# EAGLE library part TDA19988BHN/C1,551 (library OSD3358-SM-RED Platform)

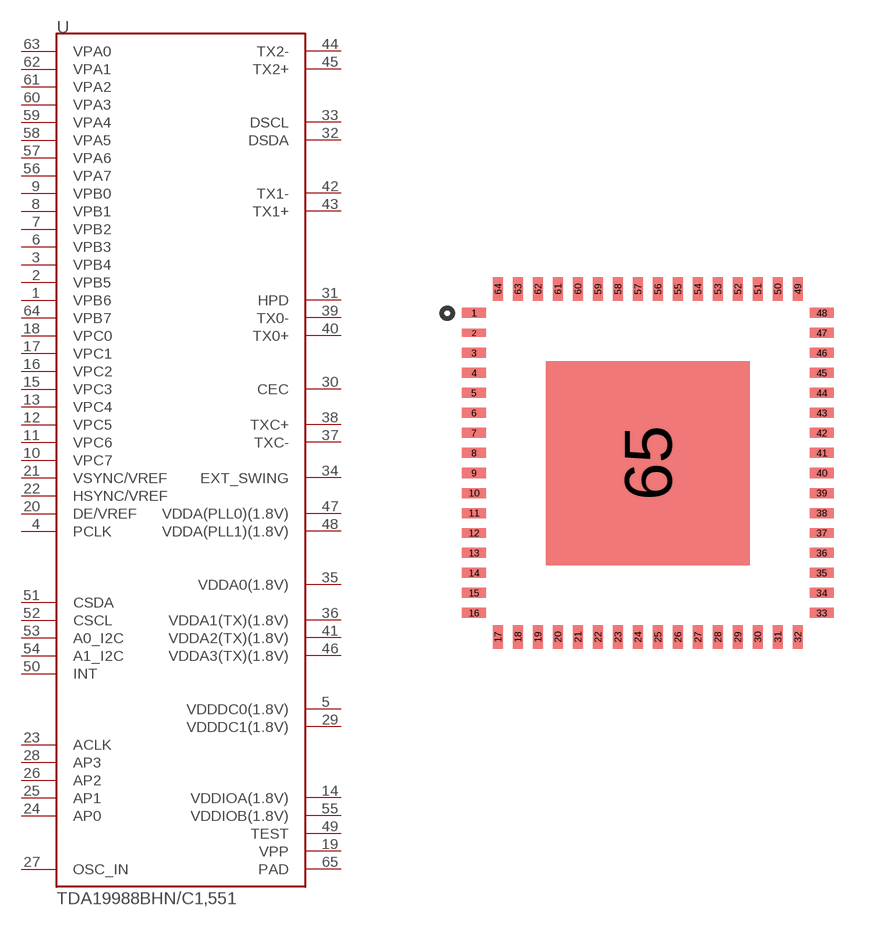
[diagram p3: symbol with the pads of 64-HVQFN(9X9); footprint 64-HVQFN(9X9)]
Designator prefix U

## TDA19988BHN/C1,551  [64-HVQFN(9X9)]
1  VPB6
2  VPB5
3  VPB4
4  PCLK
5  VDDDC0(1.8V)
6  VPB3
7  VPB2
8  VPB1
9  VPB0
10  VPC7
11  VPC6
12  VPC5
13  VPC4
14  VDDIOA(1.8V)
15  VPC3
16  VPC2
17  VPC1
18  VPC0
19  VPP
20  DE/VREF
21  VSYNC/VREF
22  HSYNC/VREF
23  ACLK
24  AP0
25  AP1
26  AP2
27  OSC_IN
28  AP3
29  VDDDC1(1.8V)
30  CEC
31  HPD
32  DSDA
33  DSCL
34  EXT_SWING
35  VDDA0(1.8V)
36  VDDA1(TX)(1.8V)
37  TXC-
38  TXC+
39  TX0-
40  TX0+
41  VDDA2(TX)(1.8V)
42  TX1-
43  TX1+
44  TX2-
45  TX2+
46  VDDA3(TX)(1.8V)
47  VDDA(PLL0)(1.8V)
48  VDDA(PLL1)(1.8V)
49  TEST
50  INT
51  CSDA
52  CSCL
53  A0_I2C
54  A1_I2C
55  VDDIOB(1.8V)
56  VPA7
57  VPA6
58  VPA5
59  VPA4
60  VPA3
61  VPA2
62  VPA1
63  VPA0
64  VPB7
65  PAD

## Footprint 64-HVQFN(9X9) (pad centres in mm)
smd 0.6 x 0.25: 1 -4.35,3.75; 3 -4.35,2.75; 4 -4.35,2.25; 5 -4.35,1.75; 6 -4.35,1.25; 7 -4.35,0.75; 8 -4.35,0.25; 9 -4.35,-0.25; 10 -4.35,-0.75; 11 -4.35,-1.25; 12 -4.35,-1.75; 13 -4.35,-2.25; 14 -4.35,-2.75; 15 -4.35,-3.25; 16 -4.35,-3.75; 33 4.35,-3.75; 34 4.35,-3.25; 35 4.35,-2.75; 36 4.35,-2.25; 37 4.35,-1.75; 38 4.35,-1.25; 39 4.35,-0.75; 40 4.35,-0.25; 41 4.35,0.25; 42 4.35,0.75; 43 4.35,1.25; 44 4.35,1.75; 45 4.35,2.25; 46 4.35,2.75; 47 4.35,3.25; 48 4.35,3.75
smd 0.6 x 0.2: 2 -4.35,3.25
smd 0.25 x 0.6: 17 -3.75,-4.35; 18 -3.25,-4.35; 19 -2.75,-4.35; 20 -2.25,-4.35; 21 -1.75,-4.35; 22 -1.25,-4.35; 23 -0.75,-4.35; 24 -0.25,-4.35; 25 0.25,-4.35; 26 0.75,-4.35; 27 1.25,-4.35; 28 1.75,-4.35; 29 2.25,-4.35; 30 2.75,-4.35; 31 3.25,-4.35; 32 3.75,-4.35; 49 3.75,4.35; 50 3.25,4.35; 51 2.75,4.35; 52 2.25,4.35; 53 1.75,4.35; 54 1.25,4.35; 55 0.75,4.35; 56 0.25,4.35; 57 -0.25,4.35; 58 -0.75,4.35; 59 -1.25,4.35; 60 -1.75,4.35; 61 -2.25,4.35; 62 -2.75,4.35; 63 -3.25,4.35; 64 -3.75,4.35
smd 5.1 x 5.1: 65 0,0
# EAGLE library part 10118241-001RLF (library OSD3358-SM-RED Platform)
Micro-HDMI connector

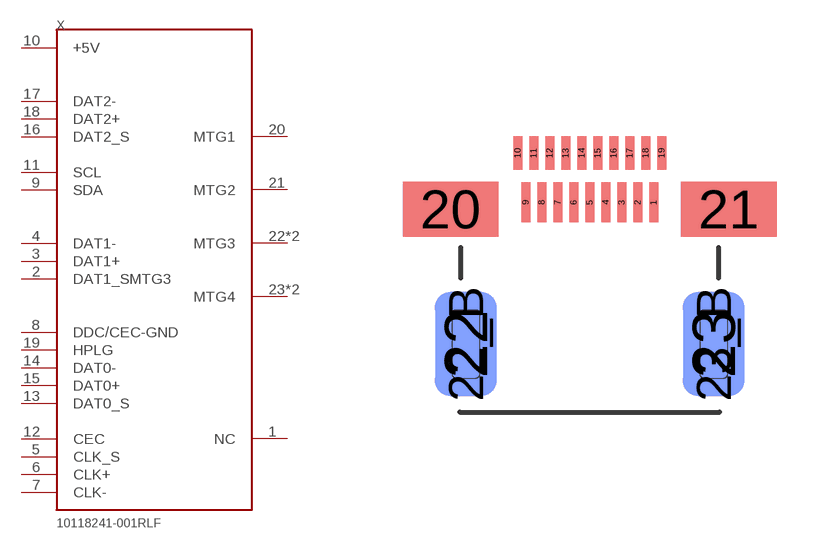
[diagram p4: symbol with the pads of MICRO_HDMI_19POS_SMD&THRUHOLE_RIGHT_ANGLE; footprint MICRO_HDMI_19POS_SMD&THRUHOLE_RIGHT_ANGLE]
Designator prefix X

## 10118241-001RLF  [MICRO_HDMI_19POS_SMD&THRUHOLE_RIGHT_ANGLE]
1  NC  nc
2  DAT1_SMTG3
3  DAT1+
4  DAT1-
5  CLK_S
6  CLK+
7  CLK-
8  DDC/CEC-GND
9  SDA
10  +5V  pwr
11  SCL
12  CEC
13  DAT0_S
14  DAT0-
15  DAT0+
16  DAT2_S
17  DAT2-
18  DAT2+
19  HPLG
20  MTG1  pwr
21  MTG2  pwr
22  MTG3  pwr
22_B  MTG3  pwr
23  MTG4  pwr
23_B  MTG4  pwr

## Footprint MICRO_HDMI_19POS_SMD&THRUHOLE_RIGHT_ANGLE (pad centres in mm)
smd 0.23 x 1: 1 1.6,3.54; 2 1.2,3.54; 3 0.8,3.54; 4 0.4,3.54; 5 0,3.54; 6 -0.4,3.54; 7 -0.8,3.54; 8 -1.2,3.54; 9 -1.6,3.54
smd 0.23 x 0.85: 10 -1.8,4.775; 11 -1.4,4.775; 12 -1,4.775; 13 -0.6,4.775; 14 -0.2,4.775; 15 0.2,4.775; 16 0.6,4.775; 17 1,4.775; 18 1.4,4.775; 19 1.8,4.775
smd 2.4 x 1.38: 20 -3.48,3.37; 21 3.48,3.37
smd 1.55 x 2.6: 22 -3.1,0; 23 3.1,0
smd 1.55 x 2.6 bottom: 22_B -3.1,0; 23_B 3.1,0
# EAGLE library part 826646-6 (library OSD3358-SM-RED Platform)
6-pin 100 mil header

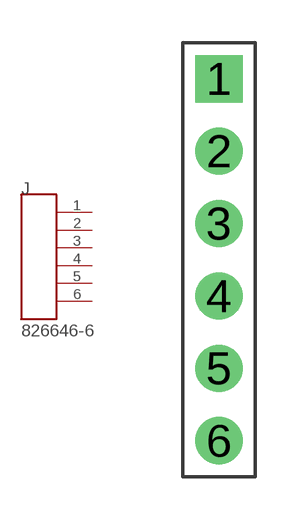
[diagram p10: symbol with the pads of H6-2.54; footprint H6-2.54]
Designator prefix J

## 826646-6 (MPN: P125-1106A1BS116A1; VALUE: 6p-2.54)  [H6-2.54]
1  1
2  2
3  3
4  4
5  5
6  6

## Footprint H6-2.54 (pad centres in mm)
drill 0.889 pad 1.651 square: 1 0,6.35
drill 0.889 pad 1.651: 2 0,3.81; 3 0,1.27; 4 0,-1.27; 5 0,-3.81; 6 0,-6.35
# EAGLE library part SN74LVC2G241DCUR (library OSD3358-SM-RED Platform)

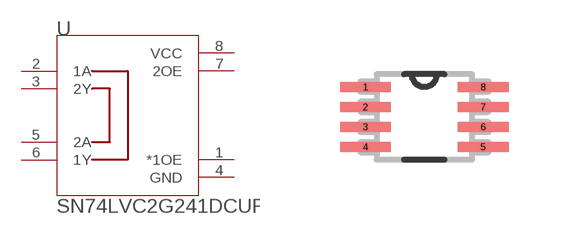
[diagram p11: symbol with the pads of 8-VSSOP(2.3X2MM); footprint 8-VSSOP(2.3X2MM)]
Designator prefix U

## SN74LVC2G241DCUR  [8-VSSOP(2.3X2MM)]
1  *1OE  in
2  1A  in
3  2Y  out
4  GND  pwr
5  2A  in
6  1Y  out
7  2OE  in
8  VCC  pwr

## Footprint 8-VSSOP(2.3X2MM) (pad centres in mm)
smd 1.27 x 0.254: 1 -1.473,0.749; 2 -1.473,0.249; 3 -1.473,-0.249; 4 -1.473,-0.749; 5 1.473,-0.749; 6 1.473,-0.249; 7 1.473,0.249; 8 1.473,0.749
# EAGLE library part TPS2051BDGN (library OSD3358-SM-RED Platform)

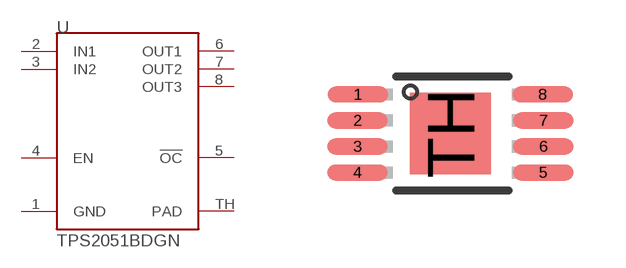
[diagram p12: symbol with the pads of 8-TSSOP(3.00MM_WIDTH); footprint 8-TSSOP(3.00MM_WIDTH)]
Designator prefix U

## TPS2051BDGN  [8-TSSOP(3.00MM_WIDTH)]
1  GND  pwr
2  IN1  in
3  IN2  in
4  EN  in
5  !OC  out
6  OUT1  out
7  OUT2  out
8  OUT3  out
TH  PAD  pwr

## Footprint 8-TSSOP(3.00MM_WIDTH) (pad centres in mm)
DGN (S-PDSO-G8) PowerPAD (TM) Plastic Small-Outline Package Source: http://focus.ti.com/lit/ds/symlink/ths4211.pdf
smd 1.524 x 0.406: 1 -2.311,0.975; 2 -2.324,0.325; 3 -2.324,-0.325; 4 -2.324,-0.975; 5 2.324,-0.975; 6 2.324,-0.325; 7 2.324,0.325; 8 2.311,0.975
smd 2.032 x 2.032: TH 0,0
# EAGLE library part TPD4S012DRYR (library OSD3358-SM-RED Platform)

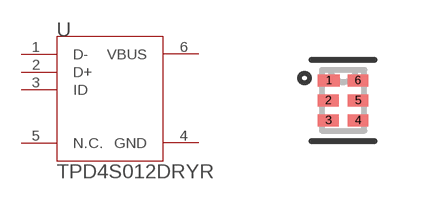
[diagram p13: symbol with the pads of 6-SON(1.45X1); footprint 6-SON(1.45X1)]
Designator prefix U

## TPD4S012DRYR_P1_M (DATASHEETURL: http://www.ti.com/lit/gpn/TPD4S012; FAMILY_NAME: ESD Solution; GENERIC_PART_NUMBER: TPD4S012; INDUSTRY_STD_PKG_TYPE: SON; MANUFACTURER: Texas Instruments; MANUFACTURER_PART_NUMBER: tpd4s012_dry_6; PACKAGE_DESIGNATOR: DRY; PIN_COUNT: 6; VENDOR: Texas Instruments)  [6-SON(1.45X1)]
1  D-  pas
2  D+  pas
3  ID  pas
4  GND  pwr
5  N.C.  nc
6  VBUS  pas

## TPD4S012DRYR_P1_P  [6-SON(1.45X1)]
1  D+  pas
2  D-  pas
3  ID  pas
4  GND  pwr
5  N.C.  nc
6  VBUS  pas

## Footprint 6-SON(1.45X1) (pad centres in mm)
smd 0.55 x 0.3: 1 -0.355,0.5
smd 0.52 x 0.3: 2 -0.37,0; 3 -0.37,-0.5; 4 0.37,-0.5; 5 0.37,0; 6 0.37,0.5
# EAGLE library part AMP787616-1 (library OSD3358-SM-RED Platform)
USB connector (horizontal)

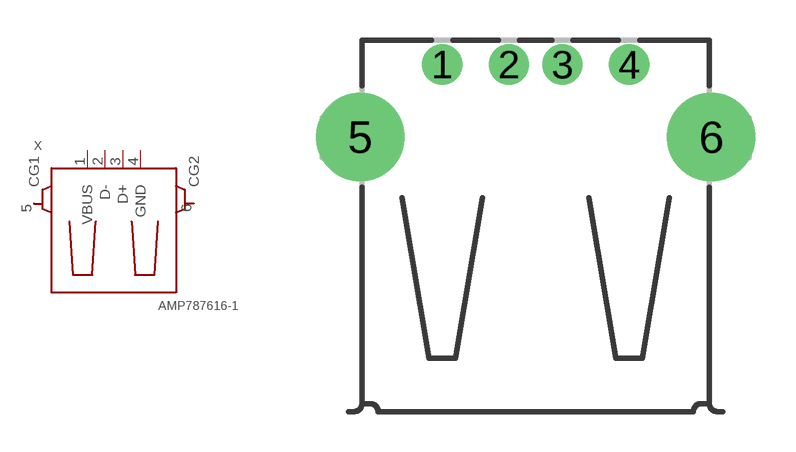
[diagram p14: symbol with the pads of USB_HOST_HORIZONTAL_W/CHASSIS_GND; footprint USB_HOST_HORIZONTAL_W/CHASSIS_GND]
Designator prefix X

## AMP787616-1  [USB_HOST_HORIZONTAL_W/CHASSIS_GND]
1  VBUS
2  D-
3  D+
4  GND
5  CG1
6  CG2

## Footprint USB_HOST_HORIZONTAL_W/CHASSIS_GND (pad centres in mm)
drill 1: 1 -3.5,12.99; 2 -1,12.99; 3 1,12.99; 4 3.5,12.99
drill 2.3: 5 -6.57,10.28; 6 6.57,10.28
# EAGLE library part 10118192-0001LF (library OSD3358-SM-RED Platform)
Amphenol FCI Micro USB Type B Complete Surface Mount (SMT) no guide holes

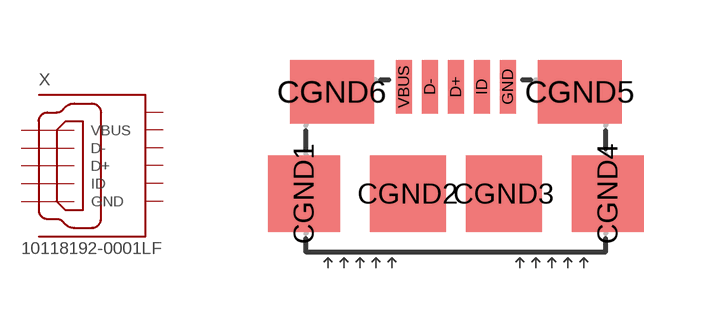
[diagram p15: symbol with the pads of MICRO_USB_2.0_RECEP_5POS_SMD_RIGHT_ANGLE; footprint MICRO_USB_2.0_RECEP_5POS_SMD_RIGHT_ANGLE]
Designator prefix X

## 10118192-0001LF  [MICRO_USB_2.0_RECEP_5POS_SMD_RIGHT_ANGLE]
CGND1  SGND1
CGND2  SGND2
CGND3  SGND3
CGND4  SGND4
CGND5  SGND5
CGND6  SGND6
D+  D+  in
D-  D-  in
GND  GND  in
ID  ID  in
VBUS  VBUS  in

## Footprint MICRO_USB_2.0_RECEP_5POS_SMD_RIGHT_ANGLE (pad centres in mm)
smd 1.8 x 1.9: CGND1 -3.8,0; CGND4 3.8,0
smd 1.9 x 1.9: CGND2 -1.2,0; CGND3 1.2,0
smd 2.1 x 1.6: CGND5 3.1,2.55; CGND6 -3.1,2.55
smd 0.4 x 1.35: D+ 0,2.675; D- -0.65,2.675; GND 1.3,2.675; ID 0.65,2.675; VBUS -1.3,2.675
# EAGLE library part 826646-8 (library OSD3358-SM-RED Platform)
8-pin 100 mil header

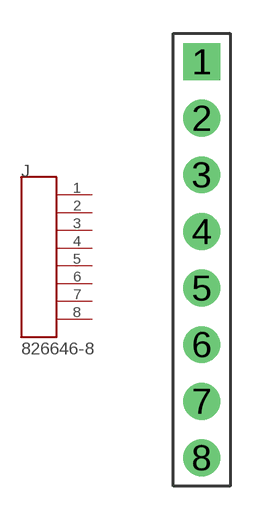
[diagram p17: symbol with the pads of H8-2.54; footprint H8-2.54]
Designator prefix J

## 826646-8  [H8-2.54]
1  1
2  2
3  3
4  4
5  5
6  6
7  7
8  8

## Footprint H8-2.54 (pad centres in mm)
drill 0.889 pad 1.651 square: 1 0,8.89
drill 0.889 pad 1.651: 2 0,6.35; 3 0,3.81; 4 0,1.27; 5 0,-1.27; 6 0,-3.81; 7 0,-6.35; 8 0,-8.89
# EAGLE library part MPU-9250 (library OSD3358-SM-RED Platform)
314990005

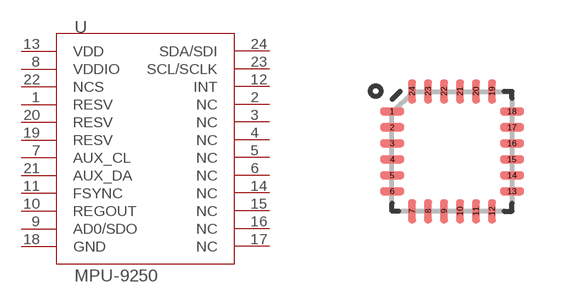
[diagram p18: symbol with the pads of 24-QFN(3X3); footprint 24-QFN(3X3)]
Designator prefix U

## MPU-9250 (MPN: MPU-9250; VALUE: MPU-9250)  [24-QFN(3X3)]
1  RESV
2  NC
3  NC
4  NC
5  NC
6  NC
7  AUX_CL
8  VDDIO
9  AD0/SDO
10  REGOUT
11  FSYNC
12  INT
13  VDD
14  NC
15  NC
16  NC
17  NC
18  GND
19  RESV
20  RESV
21  AUX_DA
22  NCS
23  SCL/SCLK
24  SDA/SDI

## Footprint 24-QFN(3X3) (pad centres in mm)
smd 0.6 x 0.2: 1 -1.5,1; 2 -1.5,0.6; 3 -1.5,0.2; 4 -1.5,-0.2; 5 -1.5,-0.6; 6 -1.5,-1; 13 1.5,-1; 14 1.5,-0.6; 15 1.5,-0.2; 16 1.5,0.2; 17 1.5,0.6; 18 1.5,1
smd 0.2 x 0.6: 7 -1,-1.5; 8 -0.6,-1.5; 9 -0.2,-1.5; 10 0.2,-1.5; 11 0.6,-1.5; 12 1,-1.5; 19 1,1.5; 20 0.6,1.5; 21 0.2,1.5; 22 -0.2,1.5; 23 -0.6,1.5; 24 -1,1.5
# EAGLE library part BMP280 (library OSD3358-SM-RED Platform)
BOSCH BMP280 Digital Pressure Sensor

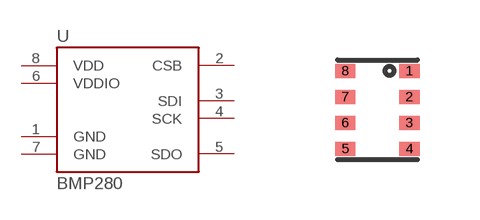
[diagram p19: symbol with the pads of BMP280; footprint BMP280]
Designator prefix U

## BMP280  [BMP280]
1  GND  pwr
2  CSB  in
3  SDI
4  SCK  in
5  SDO
6  VDDIO  in
7  GND  pwr
8  VDD  pwr

## Footprint BMP280 (pad centres in mm)
smd 0.5 x 0.35: 1 0.8,0.975; 2 0.8,0.325; 3 0.8,-0.325; 4 0.8,-0.975; 5 -0.8,-0.975; 6 -0.8,-0.325; 7 -0.8,0.325; 8 -0.8,0.975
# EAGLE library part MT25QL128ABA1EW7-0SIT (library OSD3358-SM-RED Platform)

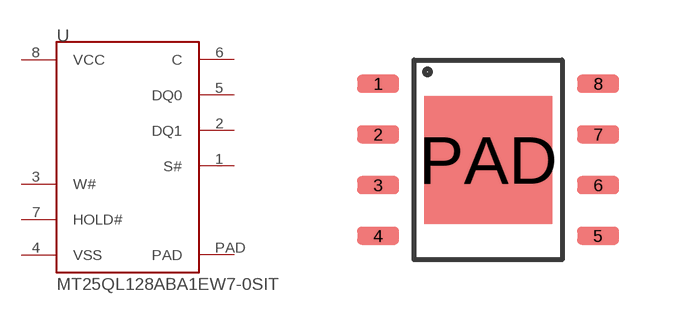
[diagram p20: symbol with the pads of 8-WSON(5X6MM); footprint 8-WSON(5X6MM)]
Designator prefix U

## MT25QL128ABA1EW7-0SIT  [8-WSON(5X6MM)]
1  S#
2  DQ1
3  W#
4  VSS
5  DQ0
6  C
7  HOLD#
8  VCC
PAD  PAD

## Footprint 8-WSON(5X6MM) (pad centres in mm)
smd 1.05 x 0.45: 1 -2.75,1.905; 2 -2.75,0.635; 3 -2.75,-0.635; 4 -2.75,-1.905; 5 2.75,-1.905; 6 2.75,-0.635; 7 2.75,0.635; 8 2.75,1.905
smd 3.2 x 3.2: PAD 0,0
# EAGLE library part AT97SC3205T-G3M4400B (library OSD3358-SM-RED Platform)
Trusted Platform Module

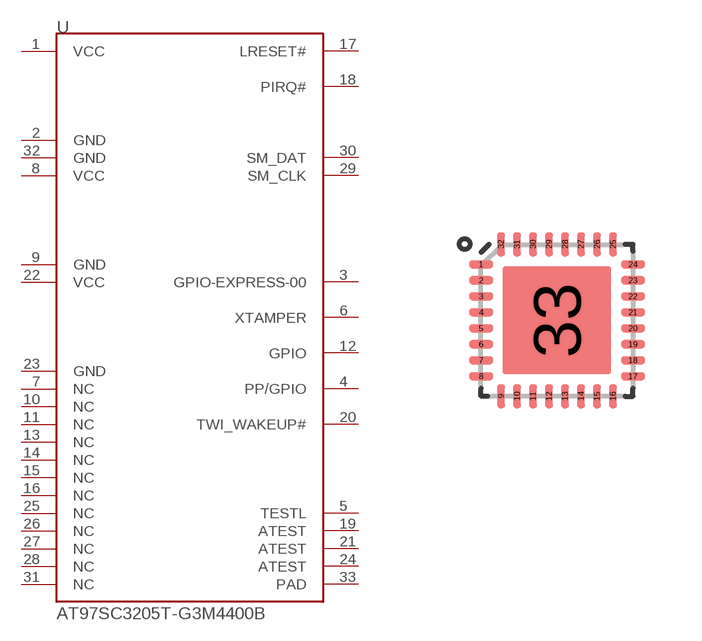
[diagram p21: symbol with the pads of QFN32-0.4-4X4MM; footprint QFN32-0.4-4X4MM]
Designator prefix U

## AT97SC3205T-G3M4400B  [QFN32-0.4-4X4MM]
1  VCC
2  GND
3  GPIO-EXPRESS-00
4  PP/GPIO
5  TESTL
6  XTAMPER
7  NC
8  VCC
9  GND
10  NC
11  NC
12  GPIO
13  NC
14  NC
15  NC
16  NC
17  LRESET#
18  PIRQ#
19  ATEST
20  TWI_WAKEUP#
21  ATEST
22  VCC
23  GND
24  ATEST
25  NC
26  NC
27  NC
28  NC
29  SM_CLK
30  SM_DAT
31  NC
32  GND
33  PAD

## Footprint QFN32-0.4-4X4MM (pad centres in mm)
smd 0.6 x 0.2: 1 -1.9,1.4; 2 -1.9,1; 3 -1.9,0.6; 4 -1.9,0.2; 5 -1.9,-0.2; 6 -1.9,-0.6; 7 -1.9,-1; 8 -1.9,-1.4; 17 1.9,-1.4; 18 1.9,-1; 19 1.9,-0.6; 20 1.9,-0.2; 21 1.9,0.2; 22 1.9,0.6; 23 1.9,1; 24 1.9,1.4
smd 0.2 x 0.6: 9 -1.4,-1.9; 10 -1,-1.9; 11 -0.6,-1.9; 12 -0.2,-1.9; 13 0.2,-1.9; 14 0.6,-1.9; 15 1,-1.9; 16 1.4,-1.9; 25 1.4,1.9; 26 1,1.9; 27 0.6,1.9; 28 0.2,1.9; 29 -0.2,1.9; 30 -0.6,1.9; 31 -1,1.9; 32 -1.4,1.9
smd 2.7 x 2.7: 33 0,0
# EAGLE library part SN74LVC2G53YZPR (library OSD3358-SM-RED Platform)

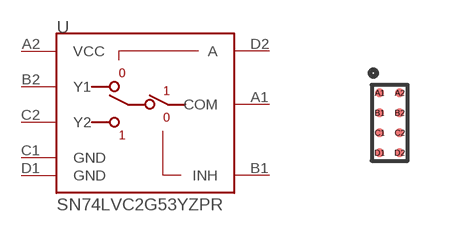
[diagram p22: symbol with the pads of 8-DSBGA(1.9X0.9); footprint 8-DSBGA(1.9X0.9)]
Designator prefix U

## SN74LVC2G53YZPR  [8-DSBGA(1.9X0.9)]
A1  COM
A2  VCC
B1  INH
B2  Y1
C1  GND
C2  Y2
D1  GND
D2  A

## Footprint 8-DSBGA(1.9X0.9) (pad centres in mm)
smd 0.23 x 0.23: A1 -0.25,0.75; A2 0.25,0.75; B1 -0.25,0.25; B2 0.25,0.25; C1 -0.25,-0.25; C2 0.25,-0.25; D1 -0.25,-0.75; D2 0.25,-0.75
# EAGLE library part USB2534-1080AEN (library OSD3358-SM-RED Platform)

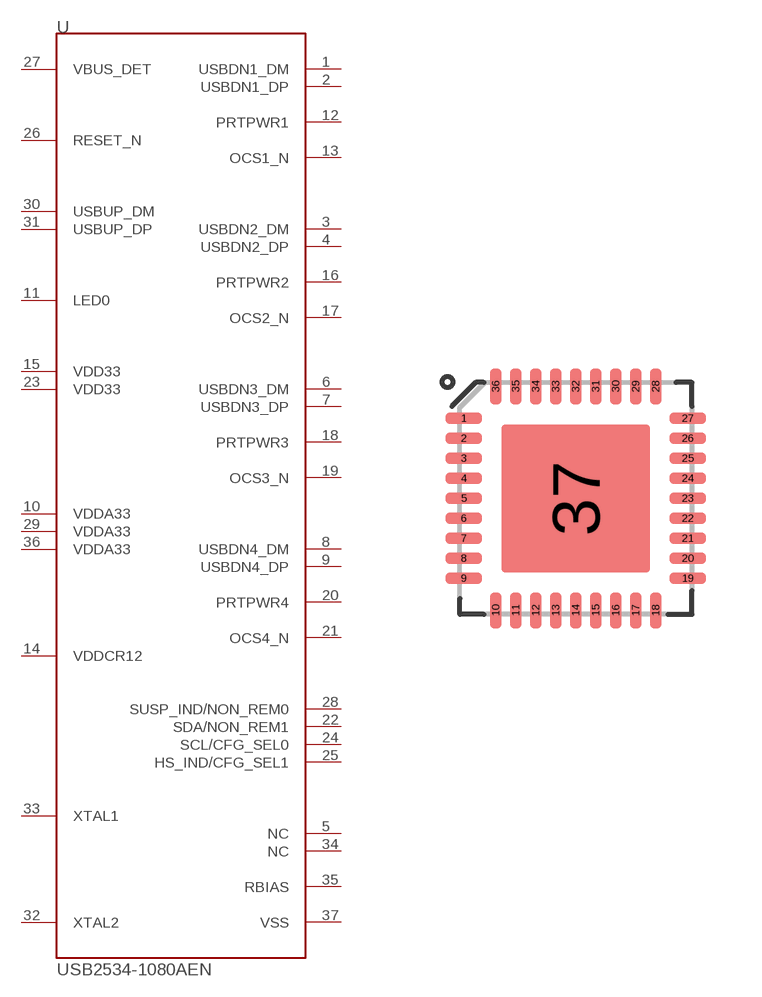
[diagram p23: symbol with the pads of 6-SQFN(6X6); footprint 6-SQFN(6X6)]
Designator prefix U

## USB2534-1080AEN  [6-SQFN(6X6)]
1  USBDN1_DM
2  USBDN1_DP
3  USBDN2_DM
4  USBDN2_DP
5  NC
6  USBDN3_DM
7  USBDN3_DP
8  USBDN4_DM
9  USBDN4_DP
10  VDDA33
11  LED0
12  PRTPWR1
13  OCS1_N
14  VDDCR12
15  VDD33
16  PRTPWR2
17  OCS2_N
18  PRTPWR3
19  OCS3_N
20  PRTPWR4
21  OCS4_N
22  SDA/NON_REM1
23  VDD33
24  SCL/CFG_SEL0
25  HS_IND/CFG_SEL1
26  RESET_N
27  VBUS_DET
28  SUSP_IND/NON_REM0
29  VDDA33
30  USBUP_DM
31  USBUP_DP
32  XTAL2
33  XTAL1
34  NC
35  RBIAS
36  VDDA33
37  VSS

## Footprint 6-SQFN(6X6) (pad centres in mm)
smd 0.9 x 0.28: 1 -2.8,2; 2 -2.8,1.5; 3 -2.8,1; 4 -2.8,0.5; 5 -2.8,0; 6 -2.8,-0.5; 7 -2.8,-1; 8 -2.8,-1.5; 9 -2.8,-2; 19 2.8,-2; 20 2.8,-1.5; 21 2.8,-1; 22 2.8,-0.5; 23 2.8,0; 24 2.8,0.5; 25 2.8,1; 26 2.8,1.5; 27 2.8,2
smd 0.28 x 0.9: 10 -2,-2.8; 11 -1.5,-2.8; 12 -1,-2.8; 13 -0.5,-2.8; 14 0,-2.8; 15 0.5,-2.8; 16 1,-2.8; 17 1.5,-2.8; 18 2,-2.8; 28 2,2.8; 29 1.5,2.8; 30 1,2.8; 31 0.5,2.8; 32 0,2.8; 33 -0.5,2.8; 34 -1,2.8; 35 -1.5,2.8; 36 -2,2.8
smd 3.7 x 3.7: 37 0,0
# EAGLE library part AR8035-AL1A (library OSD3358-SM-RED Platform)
Ethernet PHY (10/100/1000)

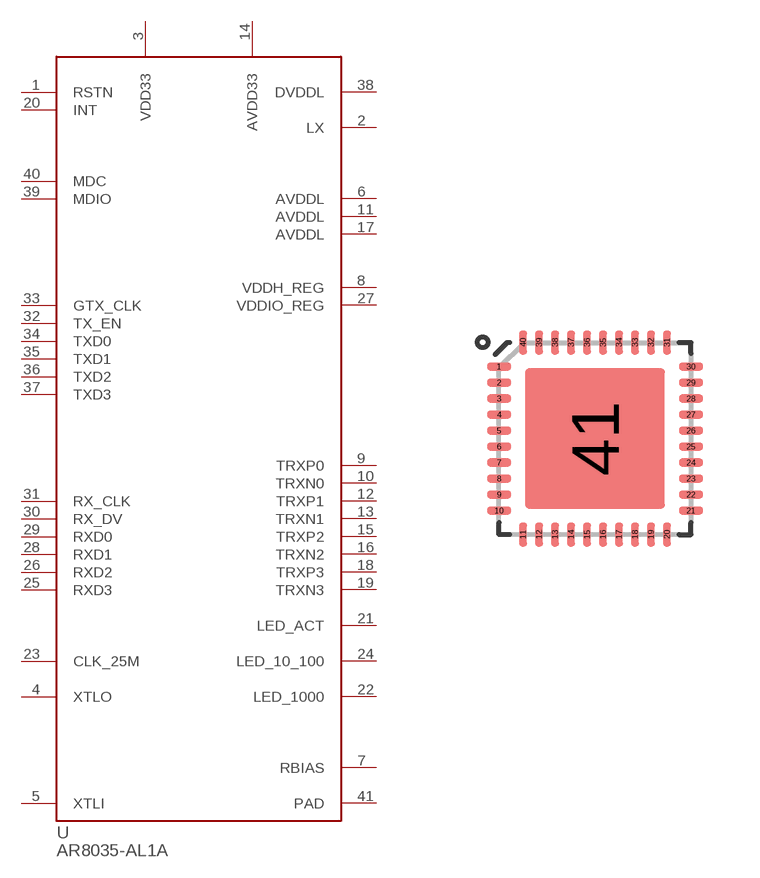
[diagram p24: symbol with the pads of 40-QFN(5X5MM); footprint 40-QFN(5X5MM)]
Designator prefix U

## AR8035-AL1A  [40-QFN(5X5MM)]
1  RSTN
2  LX
3  VDD33
4  XTLO
5  XTLI
6  AVDDL
7  RBIAS
8  VDDH_REG
9  TRXP0
10  TRXN0
11  AVDDL
12  TRXP1
13  TRXN1
14  AVDD33
15  TRXP2
16  TRXN2
17  AVDDL
18  TRXP3
19  TRXN3
20  INT
21  LED_ACT
22  LED_1000
23  CLK_25M
24  LED_10_100
25  RXD3
26  RXD2
27  VDDIO_REG
28  RXD1
29  RXD0
30  RX_DV
31  RX_CLK
32  TX_EN
33  GTX_CLK
34  TXD0
35  TXD1
36  TXD2
37  TXD3
38  DVDDL
39  MDIO
40  MDC
41  PAD

## Footprint 40-QFN(5X5MM) (pad centres in mm)
smd 0.6 x 0.2: 1 -2.4,1.8; 2 -2.4,1.4; 3 -2.4,1; 4 -2.4,0.6; 5 -2.4,0.2; 6 -2.4,-0.2; 7 -2.4,-0.6; 8 -2.4,-1; 9 -2.4,-1.4; 10 -2.4,-1.8; 21 2.4,-1.8; 22 2.4,-1.4; 23 2.4,-1; 24 2.4,-0.6; 25 2.4,-0.2; 26 2.4,0.2; 27 2.4,0.6; 28 2.4,1; 29 2.4,1.4; 30 2.4,1.8
smd 0.2 x 0.6: 11 -1.8,-2.4; 12 -1.4,-2.4; 13 -1,-2.4; 14 -0.6,-2.4; 15 -0.2,-2.4; 16 0.2,-2.4; 17 0.6,-2.4; 18 1,-2.4; 19 1.4,-2.4; 20 1.8,-2.4; 31 1.8,2.4; 32 1.4,2.4; 33 1,2.4; 34 0.6,2.4; 35 0.2,2.4; 36 -0.2,2.4; 37 -0.6,2.4; 38 -1,2.4; 39 -1.4,2.4; 40 -1.8,2.4
smd 3.5 x 3.5: 41 0,0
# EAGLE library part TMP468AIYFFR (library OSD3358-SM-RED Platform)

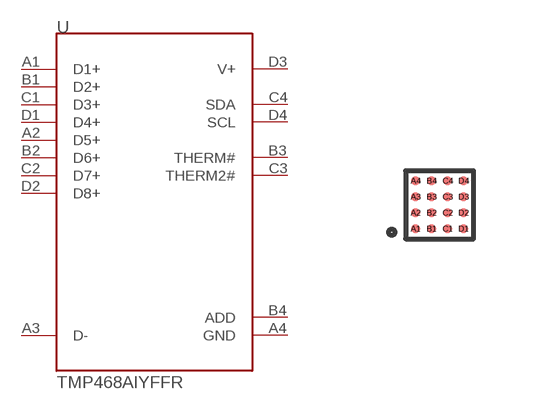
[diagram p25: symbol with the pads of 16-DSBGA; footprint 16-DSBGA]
Designator prefix U

## TMP468AIYFFR  [16-DSBGA]
A1  D1+
A2  D5+
A3  D-
A4  GND
B1  D2+
B2  D6+
B3  THERM#
B4  ADD
C1  D3+
C2  D7+
C3  THERM2#
C4  SDA
D1  D4+
D2  D8+
D3  V+
D4  SCL

## Footprint 16-DSBGA (pad centres in mm)
smd 0.23 x 0.23: A1 -0.6,-0.6; A2 -0.6,-0.2; A3 -0.6,0.2; A4 -0.6,0.6; B1 -0.2,-0.6; B2 -0.2,-0.2; B3 -0.2,0.2; B4 -0.2,0.6; C1 0.2,-0.6; C2 0.2,-0.2; C3 0.2,0.2; C4 0.2,0.6; D1 0.6,-0.6; D2 0.6,-0.2; D3 0.6,0.2; D4 0.6,0.6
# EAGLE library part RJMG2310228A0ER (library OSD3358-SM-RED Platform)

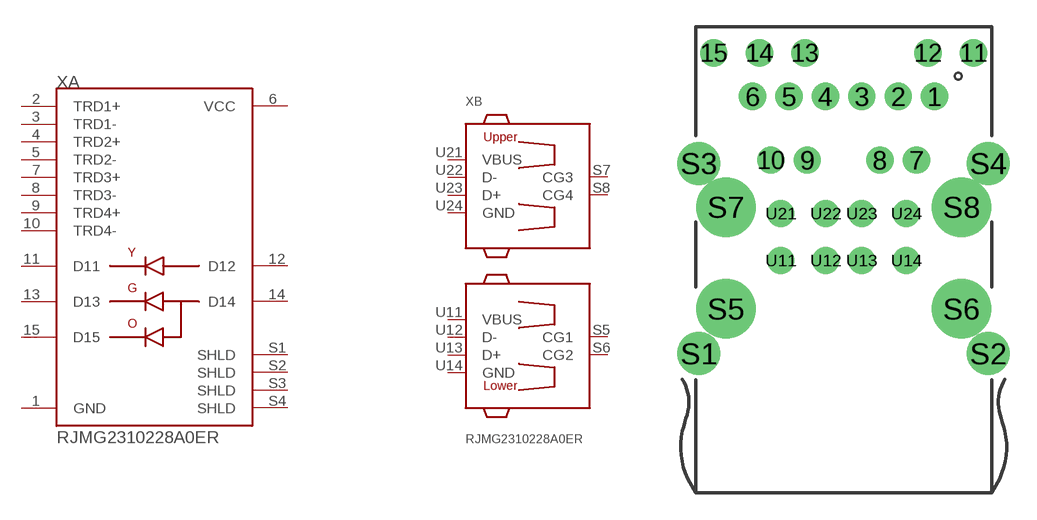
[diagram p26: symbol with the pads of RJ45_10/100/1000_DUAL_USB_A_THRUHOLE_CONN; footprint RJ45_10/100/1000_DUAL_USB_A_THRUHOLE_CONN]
Designator prefix X; gates A=RJMG23102 B=USB_HOST_W/CHASSIS_GND_DUAL

## RJMG2310228A0ER  [RJ45_10/100/1000_DUAL_USB_A_THRUHOLE_CONN]
1  A:GND
2  A:TRD1+
3  A:TRD1-
4  A:TRD2+
5  A:TRD2-
6  A:VCC
7  A:TRD3+
8  A:TRD3-
9  A:TRD4+
10  A:TRD4-
11  A:D11
12  A:D12
13  A:D13
14  A:D14
15  A:D15
S1  A:SHLD
S2  A:SHLD
S3  A:SHLD
S4  A:SHLD
S5  B:CG1
S6  B:CG2
S7  B:CG3
S8  B:CG4
U11  B:VBUS
U12  B:D-
U13  B:D+
U14  B:GND
U21  B:VBUS
U22  B:D-
U23  B:D+
U24  B:GND

## Footprint RJ45_10/100/1000_DUAL_USB_A_THRUHOLE_CONN (pad centres in mm)
Ethernet Connector (MagJack) Source: si-50170.pdf
drill 1.016 pad 1.524: 1 5.075,22.11; 2 3.045,22.11; 3 1.015,22.11; 4 -1.015,22.11; 5 -3.045,22.11; 6 -5.075,22.11; 7 4.06,18.56; 8 2.03,18.56; 9 -2.03,18.56; 10 -4.06,18.56; 11 7.24,24.55; 12 4.7,24.55; 13 -2.16,24.55; 14 -4.7,24.55; 15 -7.24,24.55
drill 1.6 pad 2.286: S1 -8.07,7.76; S2 8.07,7.76; S3 -8.07,18.38; S4 8.07,18.38
drill 2.3 pad 3: S5 -6.57,10.26; S6 6.57,10.26; S7 -6.57,15.94; S8 6.57,15.94
drill 1: U11 -3.5,12.97; U12 -1,12.97; U13 1,12.97; U14 3.5,12.97; U21 -3.5,15.59; U22 -1,15.59; U23 1,15.59; U24 3.5,15.59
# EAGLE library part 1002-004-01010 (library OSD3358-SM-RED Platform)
Dual USB connector (Horizontal)

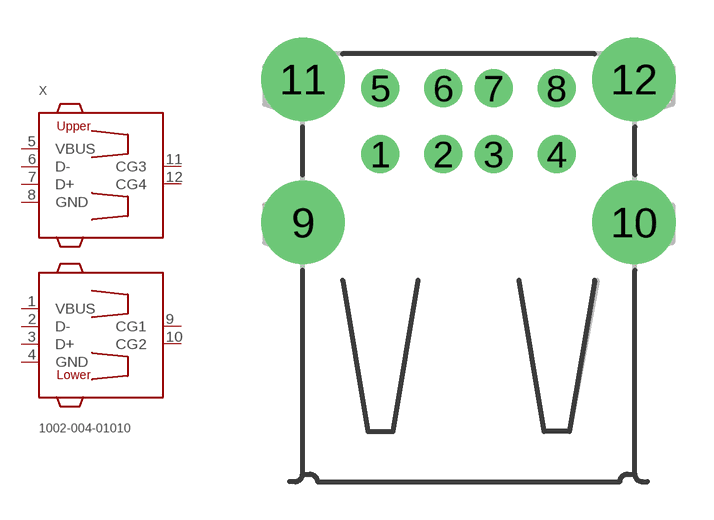
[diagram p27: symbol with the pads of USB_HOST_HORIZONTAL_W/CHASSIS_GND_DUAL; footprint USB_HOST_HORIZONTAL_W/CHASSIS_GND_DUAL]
Designator prefix X

## 1002-004-01010  [USB_HOST_HORIZONTAL_W/CHASSIS_GND_DUAL]
1  VBUS
2  D-
3  D+
4  GND
5  VBUS
6  D-
7  D+
8  GND
9  CG1
10  CG2
11  CG3
12  CG4

## Footprint USB_HOST_HORIZONTAL_W/CHASSIS_GND_DUAL (pad centres in mm)
drill 1: 1 -3.5,13.01; 2 -1,13.01; 3 1,13.01; 4 3.5,13.01; 5 -3.5,15.63; 6 -1,15.63; 7 1,15.63; 8 3.5,15.63
drill 2.3: 9 -6.57,10.3; 10 6.57,10.3; 11 -6.57,15.98; 12 6.57,15.98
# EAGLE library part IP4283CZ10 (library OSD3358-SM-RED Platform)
ESD protection for ultra high-speed interfaces

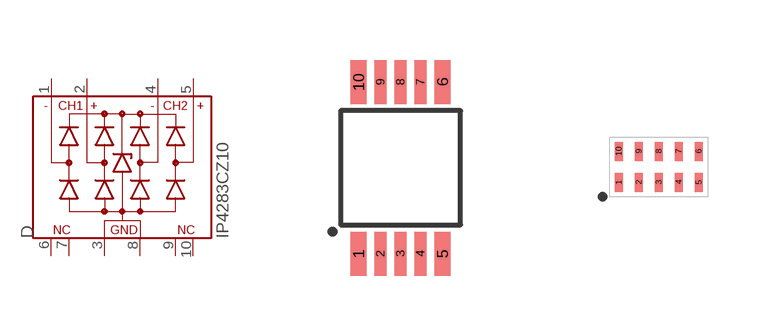
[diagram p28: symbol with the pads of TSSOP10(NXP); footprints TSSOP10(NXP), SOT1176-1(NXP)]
Designator prefix D

## IP4283CZ10  [TSSOP10(NXP)]
1  TMDS.CH1-
2  TMDS.CH1+
3  GND1
4  TMDS.CH2-
5  TMDS.CH2+
6  NC1
7  NC2
8  GND2
9  NC3
10  NC4

## IP4283CZ10IP4283CZ10-TBR  [SOT1176-1(NXP)]
Pads as for TSSOP10(NXP)

## Footprint TSSOP10(NXP) (pad centres in mm)
smd 0.4 x 1.1: 1 -1.05,-2.15; 5 1.05,-2.15; 6 1.05,2.15; 10 -1.05,2.15
smd 0.3 x 1.1: 2 -0.5,-2.15; 3 0,-2.15; 4 0.5,-2.15; 7 0.5,2.15; 8 0,2.15; 9 -0.5,2.15

## Footprint SOT1176-1(NXP) (pad centres in mm)
smd 0.2 x 0.475: 1 -1,-0.388; 2 -0.5,-0.388; 3 0,-0.388; 4 0.5,-0.388; 5 1,-0.388; 6 1,0.388; 7 0.5,0.388; 8 0,0.388; 9 -0.5,0.388; 10 -1,0.388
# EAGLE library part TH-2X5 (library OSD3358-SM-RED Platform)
320030002

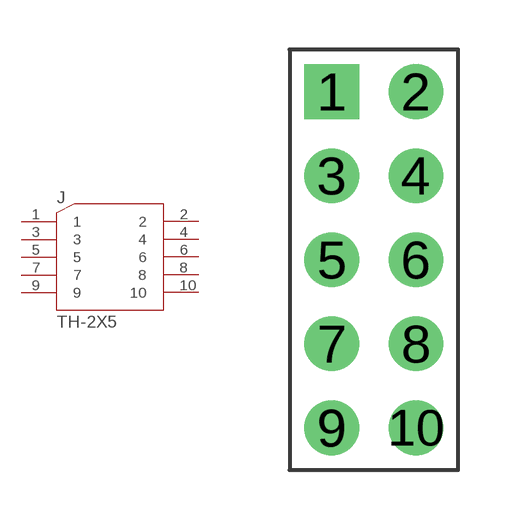
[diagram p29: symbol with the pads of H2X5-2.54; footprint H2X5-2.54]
Designator prefix J

## TH-2X5  [H2X5-2.54]
1  1
2  2
3  3
4  4
5  5
6  6
7  7
8  8
9  9
10  10

## Footprint H2X5-2.54 (pad centres in mm)
drill 0.889 pad 1.651 square: 1 -1.27,5.08
drill 0.889 pad 1.651: 2 1.27,5.08; 3 -1.27,2.54; 4 1.27,2.54; 5 -1.27,0; 6 1.27,0; 7 -1.27,-2.54; 8 1.27,-2.54; 9 -1.27,-5.08; 10 1.27,-5.08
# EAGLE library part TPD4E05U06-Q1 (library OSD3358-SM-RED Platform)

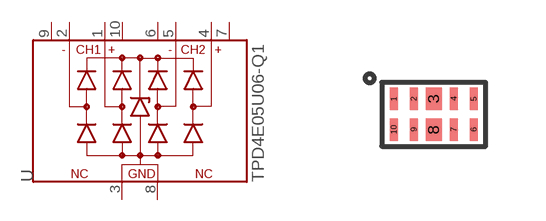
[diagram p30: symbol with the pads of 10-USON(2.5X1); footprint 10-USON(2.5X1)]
Designator prefix U

## TPD4E05U06-Q1  [10-USON(2.5X1)]
1  TMDS.CH1+
2  TMDS.CH1-
3  GND1
4  TMDS.CH2+
5  TMDS.CH2-
6  NC1
7  NC2
8  GND2
9  NC3
10  NC4

## Footprint 10-USON(2.5X1) (pad centres in mm)
smd 0.2 x 0.565: 1 -1,0.385; 2 -0.5,0.385; 4 0.5,0.385; 5 1,0.385; 6 1,-0.385; 7 0.5,-0.385; 9 -0.5,-0.385; 10 -1,-0.385
smd 0.4 x 0.565: 3 0,0.385; 8 0,-0.385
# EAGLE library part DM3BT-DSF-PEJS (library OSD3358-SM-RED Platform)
HIROSE - microSD Card socket - Reverse on-Board - Push / Push

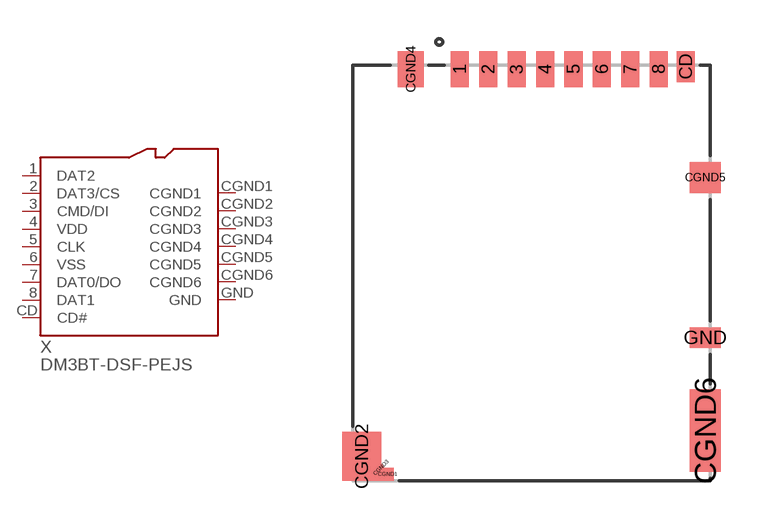
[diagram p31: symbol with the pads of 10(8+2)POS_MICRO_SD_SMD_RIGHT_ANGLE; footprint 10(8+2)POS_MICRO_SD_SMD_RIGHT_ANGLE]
Designator prefix X

## DM3BT-DSF-PEJS  [10(8+2)POS_MICRO_SD_SMD_RIGHT_ANGLE]
1  DAT2
2  DAT3/CS
3  CMD/DI
4  VDD
5  CLK
6  VSS
7  DAT0/DO
8  DAT1
CD  CD#
CGND1  CGND1
CGND2  CGND2
CGND3  CGND3
CGND4  CGND4
CGND5  CGND5
CGND6  CGND6
GND  GND

## Footprint 10(8+2)POS_MICRO_SD_SMD_RIGHT_ANGLE (pad centres in mm)
smd 0.7 x 1.4: 1 -3.2,15.95; 2 -2.1,15.95; 3 -1,15.95; 4 0.1,15.95; 5 1.2,15.95; 6 2.3,15.95; 7 3.4,15.95; 8 4.5,15.95
smd 0.7 x 1.2: CD 5.55,16.05
smd 0.5 x 0.5: CGND1 -6,0.25
smd 1.5 x 1.9: CGND2 -7,0.95
smd 0.21 x 0.21 rotated 45: CGND3 -6.25,0.5
smd 1 x 1.4: CGND4 -5.1,15.95
smd 1.2 x 1.2: CGND5 6.3,11.75
smd 1.2 x 3.2: CGND6 6.3,1.95
smd 1.2 x 0.8: GND 6.3,5.55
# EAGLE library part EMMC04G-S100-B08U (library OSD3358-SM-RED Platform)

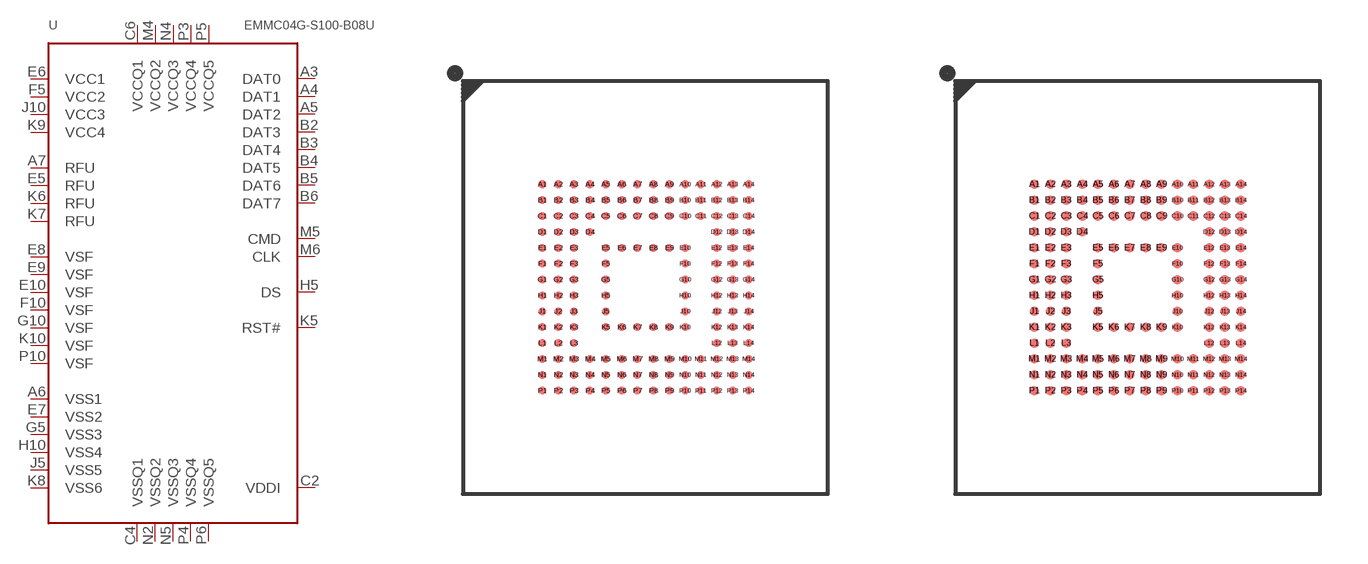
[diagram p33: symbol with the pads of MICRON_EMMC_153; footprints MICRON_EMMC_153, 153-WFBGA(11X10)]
Designator prefix U

## EMMC04G-S100-B08U  [MICRON_EMMC_153]
A3  DAT0
A4  DAT1
A5  DAT2
A6  VSS1
A7  RFU
B2  DAT3
B3  DAT4
B4  DAT5
B5  DAT6
B6  DAT7
C2  VDDI
C4  VSSQ1
C6  VCCQ1
E5  RFU
E6  VCC1
E7  VSS2
E8  VSF
E9  VSF
E10  VSF
F5  VCC2
F10  VSF
G5  VSS3
G10  VSF
H5  DS
H10  VSS4
J5  VSS5
J10  VCC3
K5  RST#
K6  RFU
K7  RFU
K8  VSS6
K9  VCC4
K10  VSF
M4  VCCQ2
M5  CMD
M6  CLK
N2  VSSQ2
N4  VCCQ3
N5  VSSQ3
P3  VCCQ4
P4  VSSQ4
P5  VCCQ5
P6  VSSQ5
P10  VSF

## EMMC04G-S100-B08U12  [153-WFBGA(11X10)]
Pads as for MICRON_EMMC_153

## Footprint MICRON_EMMC_153 (pad centres in mm)
smd 0.245 x 0.245: A1 -3.25,3.25; A2 -2.75,3.25; A3 -2.25,3.25; A4 -1.75,3.25; A5 -1.25,3.25; A6 -0.75,3.25; A7 -0.25,3.25; A8 0.25,3.25; A9 0.75,3.25; A10 1.25,3.25; A11 1.75,3.25; A12 2.25,3.25; A13 2.75,3.25; A14 3.25,3.25; B1 -3.25,2.75; B2 -2.75,2.75; B3 -2.25,2.75; B4 -1.75,2.75; B5 -1.25,2.75; B6 -0.75,2.75; B7 -0.25,2.75; B8 0.25,2.75; B9 0.75,2.75; B10 1.25,2.75; B11 1.75,2.75; B12 2.25,2.75; B13 2.75,2.75; B14 3.25,2.75; C1 -3.25,2.25; C2 -2.75,2.25; C3 -2.25,2.25; C4 -1.75,2.25; C5 -1.25,2.25; C6 -0.75,2.25; C7 -0.25,2.25; C8 0.25,2.25; C9 0.75,2.25; C10 1.25,2.25; C11 1.75,2.25; C12 2.25,2.25; C13 2.75,2.25; C14 3.25,2.25; D1 -3.25,1.75; D2 -2.75,1.75; D3 -2.25,1.75; D4 -1.75,1.75; D12 2.25,1.75; D13 2.75,1.75; D14 3.25,1.75; E1 -3.25,1.25; E2 -2.75,1.25; E3 -2.25,1.25; E5 -1.25,1.25; E6 -0.75,1.25; E7 -0.25,1.25; E8 0.25,1.25; E9 0.75,1.25; E10 1.25,1.25; E12 2.25,1.25; E13 2.75,1.25; E14 3.25,1.25; F1 -3.25,0.75; F2 -2.75,0.75; F3 -2.25,0.75; F5 -1.25,0.75; F10 1.25,0.75; F12 2.25,0.75; F13 2.75,0.75; F14 3.25,0.75; G1 -3.25,0.25; G2 -2.75,0.25; G3 -2.25,0.25; G5 -1.25,0.25; G10 1.25,0.25; G12 2.25,0.25; G13 2.75,0.25; G14 3.25,0.25; H1 -3.25,-0.25; H2 -2.75,-0.25; H3 -2.25,-0.25; H5 -1.25,-0.25; H10 1.25,-0.25; H12 2.25,-0.25; H13 2.75,-0.25; H14 3.25,-0.25; J1 -3.25,-0.75; J2 -2.75,-0.75; J3 -2.25,-0.75; J5 -1.25,-0.75; J10 1.25,-0.75; J12 2.25,-0.75; J13 2.75,-0.75; J14 3.25,-0.75; K1 -3.25,-1.25; K2 -2.75,-1.25; K3 -2.25,-1.25; K5 -1.25,-1.25; K6 -0.75,-1.25; K7 -0.25,-1.25; K8 0.25,-1.25; K9 0.75,-1.25; K10 1.25,-1.25; K12 2.25,-1.25; K13 2.75,-1.25; K14 3.25,-1.25; L1 -3.25,-1.75; L2 -2.75,-1.75; L3 -2.25,-1.75; L12 2.25,-1.75; L13 2.75,-1.75; L14 3.25,-1.75; M1 -3.25,-2.25; M2 -2.75,-2.25; M3 -2.25,-2.25; M4 -1.75,-2.25; M5 -1.25,-2.25; M6 -0.75,-2.25; M7 -0.25,-2.25; M8 0.25,-2.25; M9 0.75,-2.25; M10 1.25,-2.25; M11 1.75,-2.25; M12 2.25,-2.25; M13 2.75,-2.25; M14 3.25,-2.25; N1 -3.25,-2.75; N2 -2.75,-2.75; N3 -2.25,-2.75; N4 -1.75,-2.75; N5 -1.25,-2.75; N6 -0.75,-2.75; N7 -0.25,-2.75; N8 0.25,-2.75; N9 0.75,-2.75; N10 1.25,-2.75; N11 1.75,-2.75; N12 2.25,-2.75; N13 2.75,-2.75; N14 3.25,-2.75; P1 -3.25,-3.25; P2 -2.75,-3.25; P3 -2.25,-3.25; P4 -1.75,-3.25; P5 -1.25,-3.25; P6 -0.75,-3.25; P7 -0.25,-3.25; P8 0.25,-3.25; P9 0.75,-3.25; P10 1.25,-3.25; P11 1.75,-3.25; P12 2.25,-3.25; P13 2.75,-3.25; P14 3.25,-3.25

## Footprint 153-WFBGA(11X10) (pad centres in mm)
smd 0.305 x 0.305: A1 -3.25,3.25; A2 -2.75,3.25; A3 -2.25,3.25; A4 -1.75,3.25; A5 -1.25,3.25; A6 -0.75,3.25; A7 -0.25,3.25; A8 0.25,3.25; A9 0.75,3.25; A10 1.25,3.25; A11 1.75,3.25; A12 2.25,3.25; A13 2.75,3.25; A14 3.25,3.25; B1 -3.25,2.75; B2 -2.75,2.75; B3 -2.25,2.75; B4 -1.75,2.75; B5 -1.25,2.75; B6 -0.75,2.75; B7 -0.25,2.75; B8 0.25,2.75; B9 0.75,2.75; B10 1.25,2.75; B11 1.75,2.75; B12 2.25,2.75; B13 2.75,2.75; B14 3.25,2.75; C1 -3.25,2.25; C2 -2.75,2.25; C3 -2.25,2.25; C4 -1.75,2.25; C5 -1.25,2.25; C6 -0.75,2.25; C7 -0.25,2.25; C8 0.25,2.25; C9 0.75,2.25; C10 1.25,2.25; C11 1.75,2.25; C12 2.25,2.25; C13 2.75,2.25; C14 3.25,2.25; D1 -3.25,1.75; D2 -2.75,1.75; D3 -2.25,1.75; D4 -1.75,1.75; D12 2.25,1.75; D13 2.75,1.75; D14 3.25,1.75; E1 -3.25,1.25; E2 -2.75,1.25; E3 -2.25,1.25; E5 -1.25,1.25; E6 -0.75,1.25; E7 -0.25,1.25; E8 0.25,1.25; E9 0.75,1.25; E10 1.25,1.25; E12 2.25,1.25; E13 2.75,1.25; E14 3.25,1.25; F1 -3.25,0.75; F2 -2.75,0.75; F3 -2.25,0.75; F5 -1.25,0.75; F10 1.25,0.75; F12 2.25,0.75; F13 2.75,0.75; F14 3.25,0.75; G1 -3.25,0.25; G2 -2.75,0.25; G3 -2.25,0.25; G5 -1.25,0.25; G10 1.25,0.25; G12 2.25,0.25; G13 2.75,0.25; G14 3.25,0.25; H1 -3.25,-0.25; H2 -2.75,-0.25; H3 -2.25,-0.25; H5 -1.25,-0.25; H10 1.25,-0.25; H12 2.25,-0.25; H13 2.75,-0.25; H14 3.25,-0.25; J1 -3.25,-0.75; J2 -2.75,-0.75; J3 -2.25,-0.75; J5 -1.25,-0.75; J10 1.25,-0.75; J12 2.25,-0.75; J13 2.75,-0.75; J14 3.25,-0.75; K1 -3.25,-1.25; K2 -2.75,-1.25; K3 -2.25,-1.25; K5 -1.25,-1.25; K6 -0.75,-1.25; K7 -0.25,-1.25; K8 0.25,-1.25; K9 0.75,-1.25; K10 1.25,-1.25; K12 2.25,-1.25; K13 2.75,-1.25; K14 3.25,-1.25; L1 -3.25,-1.75; L2 -2.75,-1.75; L3 -2.25,-1.75; L12 2.25,-1.75; L13 2.75,-1.75; L14 3.25,-1.75; M1 -3.25,-2.25; M2 -2.75,-2.25; M3 -2.25,-2.25; M4 -1.75,-2.25; M5 -1.25,-2.25; M6 -0.75,-2.25; M7 -0.25,-2.25; M8 0.25,-2.25; M9 0.75,-2.25; M10 1.25,-2.25; M11 1.75,-2.25; M12 2.25,-2.25; M13 2.75,-2.25; M14 3.25,-2.25; N1 -3.25,-2.75; N2 -2.75,-2.75; N3 -2.25,-2.75; N4 -1.75,-2.75; N5 -1.25,-2.75; N6 -0.75,-2.75; N7 -0.25,-2.75; N8 0.25,-2.75; N9 0.75,-2.75; N10 1.25,-2.75; N11 1.75,-2.75; N12 2.25,-2.75; N13 2.75,-2.75; N14 3.25,-2.75; P1 -3.25,-3.25; P2 -2.75,-3.25; P3 -2.25,-3.25; P4 -1.75,-3.25; P5 -1.25,-3.25; P6 -0.75,-3.25; P7 -0.25,-3.25; P8 0.25,-3.25; P9 0.75,-3.25; P10 1.25,-3.25; P11 1.75,-3.25; P12 2.25,-3.25; P13 2.75,-3.25; P14 3.25,-3.25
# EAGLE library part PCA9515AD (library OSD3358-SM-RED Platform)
DUAL BIDIRECTIONAL I2C BUS AND SMBus REPEATER

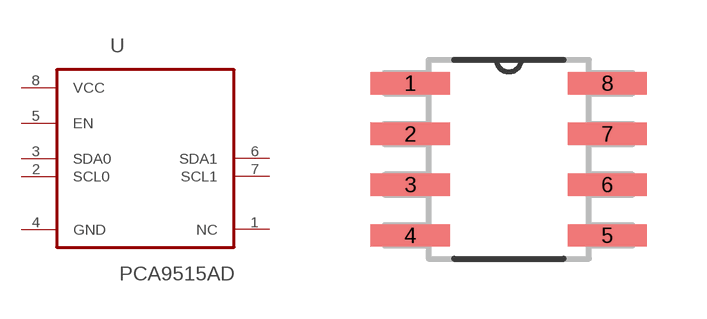
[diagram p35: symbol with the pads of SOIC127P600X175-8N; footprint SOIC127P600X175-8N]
Designator prefix U

## PCA9515AD (AVAILABILITY: Unavailable; DESCRIPTION: Buffer, ReDriver 1 Channel 400kHz 8-SOIC; MF: Texas Instruments; MP: PCA9515AD; PACKAGE: SOIC-8 Texas Instruments; PRICE: None)  [SOIC127P600X175-8N]
1  NC  nc
2  SCL0  out
3  SDA0  out
4  GND  pas
5  EN  in
6  SDA1  out
7  SCL1  out
8  VCC  pwr

## Footprint SOIC127P600X175-8N (pad centres in mm)
smd 1.981 x 0.559: 1 -2.464,1.905; 2 -2.464,0.635; 3 -2.464,-0.635; 4 -2.464,-1.905; 5 2.464,-1.905; 6 2.464,-0.635; 7 2.464,0.635; 8 2.464,1.905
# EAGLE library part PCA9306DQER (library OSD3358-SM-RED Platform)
Check prices

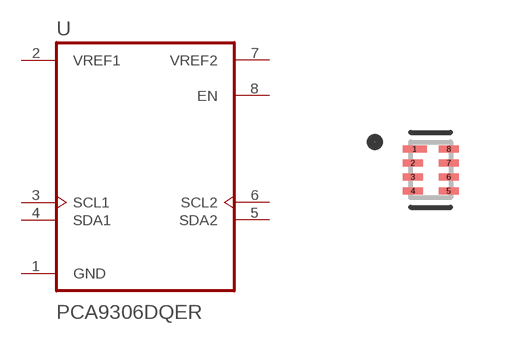
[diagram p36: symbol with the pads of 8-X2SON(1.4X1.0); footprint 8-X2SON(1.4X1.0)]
Designator prefix U

## PCA9306DQER (AVAILABILITY: Good; DESCRIPTION: 2-bit bidirectional I2C bus and SMBus voltage-level shifter 8-X2SON -40 to 85; MF: Texas Instruments; MP: PCA9306DQER; PACKAGE: X2SON-8 Texas Instruments; PRICE: None; PURCHASE-URL: https://pricing.snapeda.com/search/part/PCA9306DQER/?ref=eda)  [8-X2SON(1.4X1.0)]
1  GND  pwr
2  VREF1  in
3  SCL1  in
4  SDA1
5  SDA2
6  SCL2  in
7  VREF2  in
8  EN  in

## Footprint 8-X2SON(1.4X1.0) (pad centres in mm)
smd 0.6 x 0.175: 1 -0.4,0.525
smd 0.5 x 0.175: 2 -0.45,0.175; 3 -0.45,-0.175; 4 -0.45,-0.525; 5 0.45,-0.525; 6 0.45,-0.175; 7 0.45,0.175; 8 0.45,0.525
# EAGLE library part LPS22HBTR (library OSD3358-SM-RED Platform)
Pressure Sensor 3.77PSI ~ 18.27PSI (26kPa ~ 126kPa) Absolute 24 b 10-WFLGA Exposed Pad Check prices

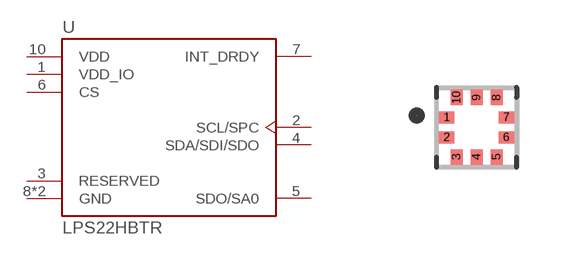
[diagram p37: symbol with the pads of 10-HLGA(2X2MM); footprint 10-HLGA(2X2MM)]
Designator prefix U

## LPS22HBTR (AVAILABILITY: Good; DESCRIPTION: Pressure Sensor 3.77PSI ~ 18.27PSI (26kPa ~ 126kPa) Absolute 24 b 10-WFLGA Exposed Pad; MF: STMicroelectronics; MP: LPS22HBTR; PACKAGE: WFLGA-10 STMicroelectronics; PRICE: None; PURCHASE-URL: https://pricing.snapeda.com/search/part/LPS22HBTR/?ref=eda)  [10-HLGA(2X2MM)]
1  VDD_IO  pwr
2  SCL/SPC  in
3  RESERVED  pas
4  SDA/SDI/SDO
5  SDO/SA0
6  CS  in
7  INT_DRDY  out
8  GND  pwr
9  GND  pwr
10  VDD  pwr

## Footprint 10-HLGA(2X2MM) (pad centres in mm)
smd 0.387 x 0.3: 1 -0.745,0.25; 2 -0.745,-0.25; 6 0.745,-0.25; 7 0.745,0.25
smd 0.3 x 0.387: 3 -0.5,-0.745; 4 0,-0.745; 5 0.5,-0.745; 8 0.5,0.745; 9 0,0.745; 10 -0.5,0.745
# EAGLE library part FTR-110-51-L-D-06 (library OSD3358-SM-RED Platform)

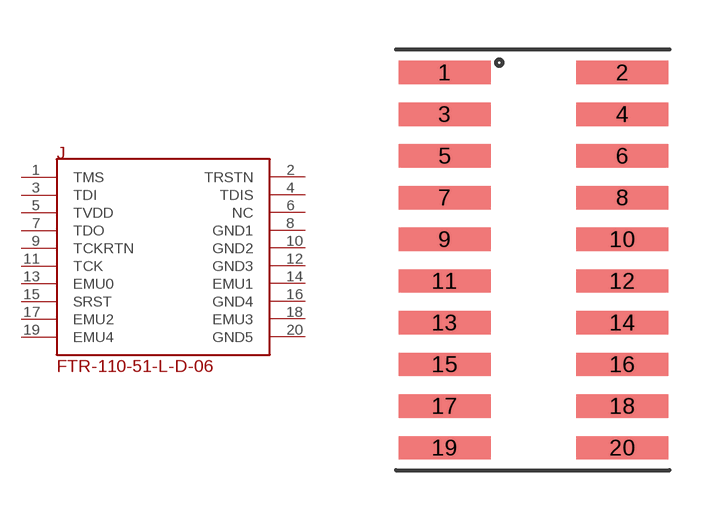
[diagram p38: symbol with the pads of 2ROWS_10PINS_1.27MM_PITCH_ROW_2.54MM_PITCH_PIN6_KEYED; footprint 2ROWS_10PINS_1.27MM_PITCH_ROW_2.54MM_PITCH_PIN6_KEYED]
Designator prefix J

## FTR-110-51-L-D-06  [2ROWS_10PINS_1.27MM_PITCH_ROW_2.54MM_PITCH_PIN6_KEYED]
1  TMS
2  TRSTN
3  TDI
4  TDIS
5  TVDD
6  NC
7  TDO
8  GND1
9  TCKRTN
10  GND2
11  TCK
12  GND3
13  EMU0
14  EMU1
15  SRST
16  GND4
17  EMU2
18  EMU3
19  EMU4
20  GND5

## Footprint 2ROWS_10PINS_1.27MM_PITCH_ROW_2.54MM_PITCH_PIN6_KEYED (pad centres in mm)
smd 2.794 x 0.711: 1 -2.705,5.715; 2 2.705,5.715; 3 -2.705,4.445; 4 2.705,4.445; 5 -2.705,3.175; 6 2.705,3.175; 7 -2.705,1.905; 8 2.705,1.905; 9 -2.705,0.635; 10 2.705,0.635; 11 -2.705,-0.635; 12 2.705,-0.635; 13 -2.705,-1.905; 14 2.705,-1.905; 15 -2.705,-3.175; 16 2.705,-3.175; 17 -2.705,-4.445; 18 2.705,-4.445; 19 -2.705,-5.715; 20 2.705,-5.715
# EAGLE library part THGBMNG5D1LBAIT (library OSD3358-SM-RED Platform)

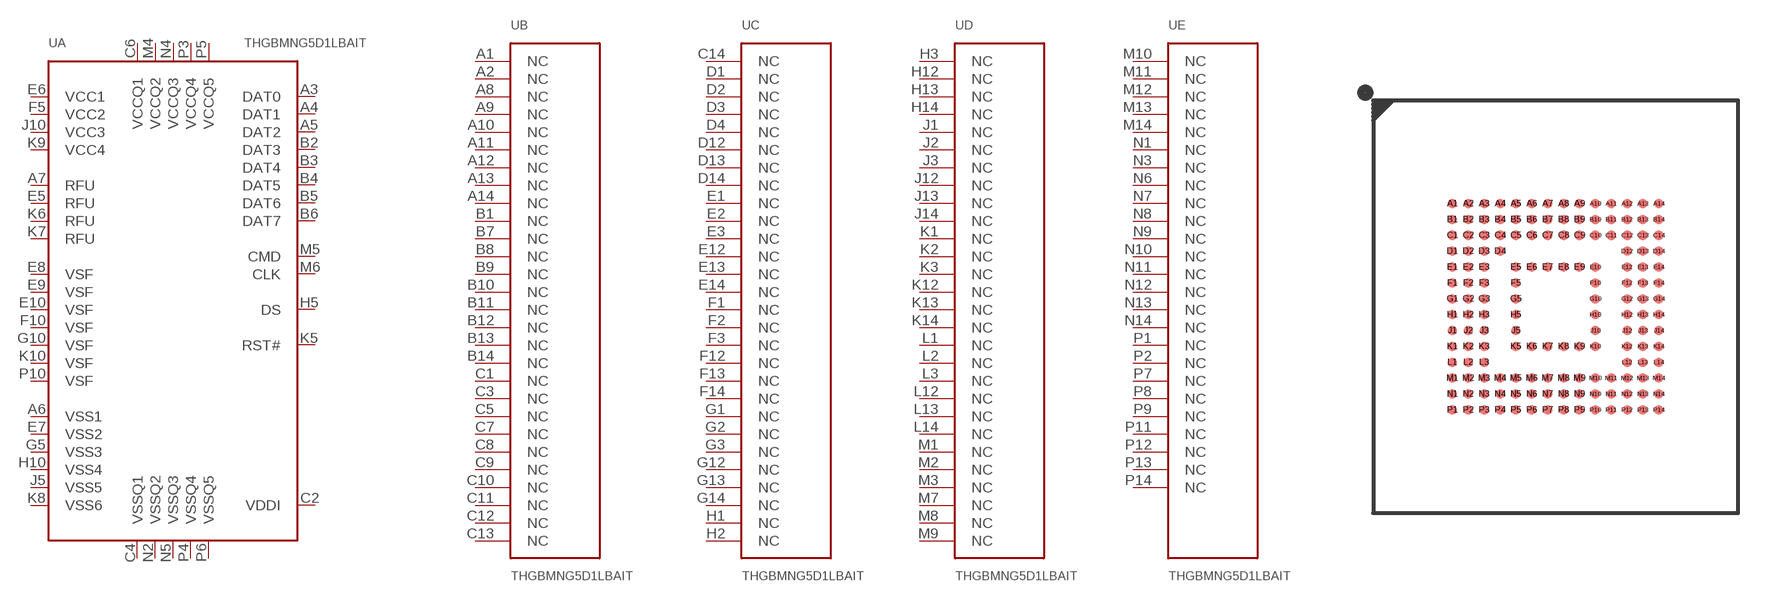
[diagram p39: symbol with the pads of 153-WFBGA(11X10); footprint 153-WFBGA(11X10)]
Designator prefix U; gates A=EMMC_5.X_153 B=EMMC_5.X_153-NC-1 C=EMMC_5.X_153-NC-2 D=EMMC_5.X_153-NC-3 E=EMMC_5.X_153-NC-4

## THGBMNG5D1LBAIT  [153-WFBGA(11X10)]
A1  B:NC
A2  B:NC
A3  A:DAT0
A4  A:DAT1
A5  A:DAT2
A6  A:VSS1
A7  A:RFU
A8  B:NC
A9  B:NC
A10  B:NC
A11  B:NC
A12  B:NC
A13  B:NC
A14  B:NC
B1  B:NC
B2  A:DAT3
B3  A:DAT4
B4  A:DAT5
B5  A:DAT6
B6  A:DAT7
B7  B:NC
B8  B:NC
B9  B:NC
B10  B:NC
B11  B:NC
B12  B:NC
B13  B:NC
B14  B:NC
C1  B:NC
C2  A:VDDI
C3  B:NC
C4  A:VSSQ1
C5  B:NC
C6  A:VCCQ1
C7  B:NC
C8  B:NC
C9  B:NC
C10  B:NC
C11  B:NC
C12  B:NC
C13  B:NC
C14  C:NC
D1  C:NC
D2  C:NC
D3  C:NC
D4  C:NC
D12  C:NC
D13  C:NC
D14  C:NC
E1  C:NC
E2  C:NC
E3  C:NC
E5  A:RFU
E6  A:VCC1
E7  A:VSS2
E8  A:VSF
E9  A:VSF
E10  A:VSF
E12  C:NC
E13  C:NC
E14  C:NC
F1  C:NC
F2  C:NC
F3  C:NC
F5  A:VCC2
F10  A:VSF
F12  C:NC
F13  C:NC
F14  C:NC
G1  C:NC
G2  C:NC
G3  C:NC
G5  A:VSS3
G10  A:VSF
G12  C:NC
G13  C:NC
G14  C:NC
H1  C:NC
H2  C:NC
H3  D:NC
H5  A:DS
H10  A:VSS4
H12  D:NC
H13  D:NC
H14  D:NC
J1  D:NC
J2  D:NC
J3  D:NC
J5  A:VSS5
J10  A:VCC3
J12  D:NC
J13  D:NC
J14  D:NC
K1  D:NC
K2  D:NC
K3  D:NC
K5  A:RST#
K6  A:RFU
K7  A:RFU
K8  A:VSS6
K9  A:VCC4
K10  A:VSF
K12  D:NC
K13  D:NC
K14  D:NC
L1  D:NC
L2  D:NC
L3  D:NC
L12  D:NC
L13  D:NC
L14  D:NC
M1  D:NC
M2  D:NC
M3  D:NC
M4  A:VCCQ2
M5  A:CMD
M6  A:CLK
M7  D:NC
M8  D:NC
M9  D:NC
M10  E:NC
M11  E:NC
M12  E:NC
M13  E:NC
M14  E:NC
N1  E:NC
N2  A:VSSQ2
N3  E:NC
N4  A:VCCQ3
N5  A:VSSQ3
N6  E:NC
N7  E:NC
N8  E:NC
N9  E:NC
N10  E:NC
N11  E:NC
N12  E:NC
N13  E:NC
N14  E:NC
P1  E:NC
P2  E:NC
P3  A:VCCQ4
P4  A:VSSQ4
P5  A:VCCQ5
P6  A:VSSQ5
P7  E:NC
P8  E:NC
P9  E:NC
P10  A:VSF
P11  E:NC
P12  E:NC
P13  E:NC
P14  E:NC

## Footprint 153-WFBGA(11X10) (pad centres in mm)
smd 0.305 x 0.305: A1 -3.25,3.25; A2 -2.75,3.25; A3 -2.25,3.25; A4 -1.75,3.25; A5 -1.25,3.25; A6 -0.75,3.25; A7 -0.25,3.25; A8 0.25,3.25; A9 0.75,3.25; A10 1.25,3.25; A11 1.75,3.25; A12 2.25,3.25; A13 2.75,3.25; A14 3.25,3.25; B1 -3.25,2.75; B2 -2.75,2.75; B3 -2.25,2.75; B4 -1.75,2.75; B5 -1.25,2.75; B6 -0.75,2.75; B7 -0.25,2.75; B8 0.25,2.75; B9 0.75,2.75; B10 1.25,2.75; B11 1.75,2.75; B12 2.25,2.75; B13 2.75,2.75; B14 3.25,2.75; C1 -3.25,2.25; C2 -2.75,2.25; C3 -2.25,2.25; C4 -1.75,2.25; C5 -1.25,2.25; C6 -0.75,2.25; C7 -0.25,2.25; C8 0.25,2.25; C9 0.75,2.25; C10 1.25,2.25; C11 1.75,2.25; C12 2.25,2.25; C13 2.75,2.25; C14 3.25,2.25; D1 -3.25,1.75; D2 -2.75,1.75; D3 -2.25,1.75; D4 -1.75,1.75; D12 2.25,1.75; D13 2.75,1.75; D14 3.25,1.75; E1 -3.25,1.25; E2 -2.75,1.25; E3 -2.25,1.25; E5 -1.25,1.25; E6 -0.75,1.25; E7 -0.25,1.25; E8 0.25,1.25; E9 0.75,1.25; E10 1.25,1.25; E12 2.25,1.25; E13 2.75,1.25; E14 3.25,1.25; F1 -3.25,0.75; F2 -2.75,0.75; F3 -2.25,0.75; F5 -1.25,0.75; F10 1.25,0.75; F12 2.25,0.75; F13 2.75,0.75; F14 3.25,0.75; G1 -3.25,0.25; G2 -2.75,0.25; G3 -2.25,0.25; G5 -1.25,0.25; G10 1.25,0.25; G12 2.25,0.25; G13 2.75,0.25; G14 3.25,0.25; H1 -3.25,-0.25; H2 -2.75,-0.25; H3 -2.25,-0.25; H5 -1.25,-0.25; H10 1.25,-0.25; H12 2.25,-0.25; H13 2.75,-0.25; H14 3.25,-0.25; J1 -3.25,-0.75; J2 -2.75,-0.75; J3 -2.25,-0.75; J5 -1.25,-0.75; J10 1.25,-0.75; J12 2.25,-0.75; J13 2.75,-0.75; J14 3.25,-0.75; K1 -3.25,-1.25; K2 -2.75,-1.25; K3 -2.25,-1.25; K5 -1.25,-1.25; K6 -0.75,-1.25; K7 -0.25,-1.25; K8 0.25,-1.25; K9 0.75,-1.25; K10 1.25,-1.25; K12 2.25,-1.25; K13 2.75,-1.25; K14 3.25,-1.25; L1 -3.25,-1.75; L2 -2.75,-1.75; L3 -2.25,-1.75; L12 2.25,-1.75; L13 2.75,-1.75; L14 3.25,-1.75; M1 -3.25,-2.25; M2 -2.75,-2.25; M3 -2.25,-2.25; M4 -1.75,-2.25; M5 -1.25,-2.25; M6 -0.75,-2.25; M7 -0.25,-2.25; M8 0.25,-2.25; M9 0.75,-2.25; M10 1.25,-2.25; M11 1.75,-2.25; M12 2.25,-2.25; M13 2.75,-2.25; M14 3.25,-2.25; N1 -3.25,-2.75; N2 -2.75,-2.75; N3 -2.25,-2.75; N4 -1.75,-2.75; N5 -1.25,-2.75; N6 -0.75,-2.75; N7 -0.25,-2.75; N8 0.25,-2.75; N9 0.75,-2.75; N10 1.25,-2.75; N11 1.75,-2.75; N12 2.25,-2.75; N13 2.75,-2.75; N14 3.25,-2.75; P1 -3.25,-3.25; P2 -2.75,-3.25; P3 -2.25,-3.25; P4 -1.75,-3.25; P5 -1.25,-3.25; P6 -0.75,-3.25; P7 -0.25,-3.25; P8 0.25,-3.25; P9 0.75,-3.25; P10 1.25,-3.25; P11 1.75,-3.25; P12 2.25,-3.25; P13 2.75,-3.25; P14 3.25,-3.25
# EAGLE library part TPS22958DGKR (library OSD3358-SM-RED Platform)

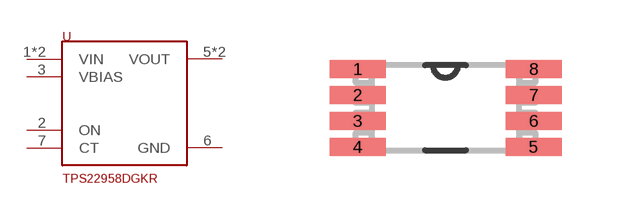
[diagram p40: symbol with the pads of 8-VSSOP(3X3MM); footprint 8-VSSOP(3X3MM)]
Designator prefix U

## TPS22958DGKR  [8-VSSOP(3X3MM)]
1  VIN
2  ON
3  VBIAS
4  VIN
5  VOUT
6  GND
7  CT
8  VOUT

## Footprint 8-VSSOP(3X3MM) (pad centres in mm)
smd 1.4 x 0.45: 1 -2.2,0.975; 2 -2.2,0.325; 3 -2.2,-0.325; 4 -2.2,-0.975; 5 2.2,-0.975; 6 2.2,-0.325; 7 2.2,0.325; 8 2.2,0.975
